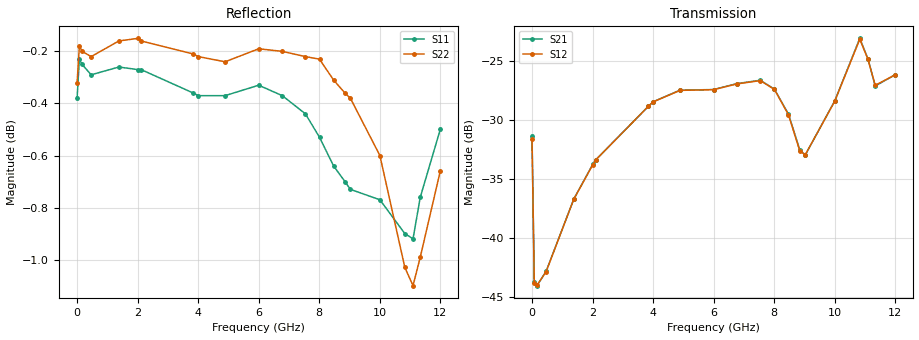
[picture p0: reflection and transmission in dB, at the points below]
!Agilent Technologies,E5071C,MY46418240,A.11.23
!Date: Wed Dec 09 09:53:53 2020
!Data & Calibration Information:
!Freq	S11:SOLT2(ON)	S21:SOLT2(ON)	S12:SOLT2(ON)	S22:SOLT2(ON)
!PortZ  Port1:50+j0  Port2:50+j0
!Above PortZ is port z conversion or system Z0 setting when saving the data.
!When reading, reference impedance value at option line is always used.
# Hz S dB R 50
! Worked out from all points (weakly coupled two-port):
!   801 points, 300 kHz to 12 GHz, reference 50 ohm
!   highest |S21| = -23.11 dB at 10.83 GHz (marker M1); lowest = -44.0 dB at 165.3 MHz (marker M2)
!   lowest |S11| = -0.9 dB at 11.1 GHz (marker M3), VSWR 18.98, Z = 7.51 + j67.8 ohm
!   |S11| at or under -10 dB: nowhere
!   |S22| runs from -1.2 to -0.1 dB; largest |S21 - S12| = 0.0012
!   S11 on the Smith chart (normalised r, x): 300 kHz: 0.02, -0.01; 2.115 GHz: 0.02, +0.20; 3.84 GHz: 0.02, +0.42; 6.78 GHz: 0.03, +0.68; 9.03 GHz: 0.09, +1.03; 12 GHz: 0.10, +1.51
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300000  -0.38 -179.4  -31.37 -24.4  -31.66 -22.8  -0.32 -179.5
7.529812e7  -0.23 178.9  -43.75 -1.2  -43.79 -1.6  -0.18 179.1
1.652959e8  -0.25 177.9  -44.03 7.9  -43.99 7.7  -0.20 178.4
4.652884e8  -0.29 175.2  -42.82 30.8  -42.85 31.4  -0.22 176.8
1.380266e9  -0.26 166.9  -36.71 55.7  -36.71 55.9  -0.16 171.9
2.01025e9  -0.27 159.3  -33.75 56.5  -33.79 56.4  -0.15 167.3
2.115247e9  -0.27 157.9  -33.36 56.4  -33.37 56.3  -0.16 166.5
3.840204e9  -0.36 134.8  -28.87 49.1  -28.87 49.1  -0.21 152.6
4.0052e9  -0.37 132.3  -28.47 47.0  -28.48 47.1  -0.22 150.6
4.890178e9  -0.37 121.7  -27.49 35.9  -27.51 35.8  -0.24 139.6
6.00015e9  -0.33 117.1  -27.44 27.8  -27.45 27.8  -0.19 132.0
6.78013e9  -0.37 111.7  -26.93 22.5  -26.96 22.5  -0.20 126.0
7.545111e9  -0.44 105.7  -26.65 11.0  -26.68 10.9  -0.22 121.6
8.0101e9  -0.53 101.8  -27.41 0.6  -27.43 0.5  -0.23 120.7
8.475088e9  -0.64 95.6  -29.52 -6.3  -29.58 -6.0  -0.31 119.8
8.850079e9  -0.70 90.6  -32.55 1.9  -32.65 2.8  -0.36 116.9
9.030074e9  -0.73 88.1  -32.97 15.3  -32.95 16.0  -0.38 115.3
1.000505e10  -0.77 80.3  -28.39 36.7  -28.42 36.9  -0.60 109.2
1.083003e10  -0.90 75.1  -23.11 9.4  -23.18 9.8  -1.03 107.2
1.110002e10  -0.92 72.4  -24.83 -9.1  -24.87 -8.6  -1.10 106.3
1.134002e10  -0.76 70.5  -27.14 -4.5  -27.08 -4.1  -0.99 103.7
1.2e10  -0.50 66.7  -26.19 -8.9  -26.19 -8.6  -0.66 95.5
